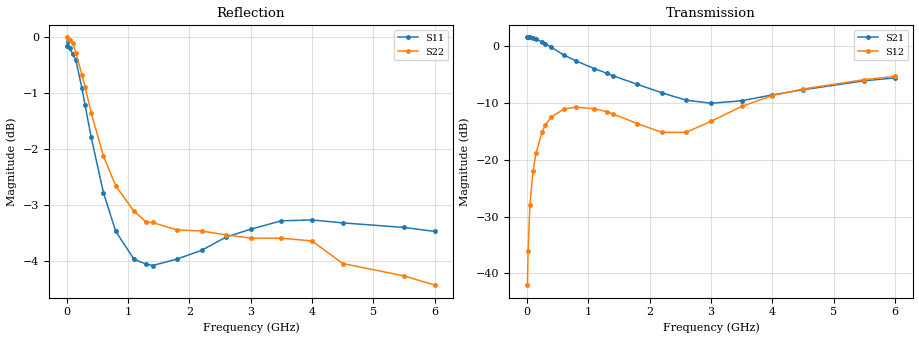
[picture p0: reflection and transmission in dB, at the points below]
! Infineon Technologies  Discrete & RF Semiconductors
! BFS17W
! Si NPN RF Bipolar Junction Transistor in SOT323
! VCE = 0.5 V  IC = 0.3 mA
! Common Emitter S-Parameters:  August  1999
# GHz  S  MA  R  50
!  f  S11  S21  S12  S22
! GHz  MAG  ANG  MAG  ANG  MAG  ANG  MAG  ANG
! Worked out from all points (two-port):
!   36 points, 10 MHz to 6 GHz, reference 50 ohm
!   highest |S21| = 1.55 dB at 20 MHz (marker M1); lowest = -10.0 dB at 3 GHz (marker M2)
!   |S21| within 3 dB of the highest: start of sweep to 586.2 MHz
!   lowest |S11| = -4.1 dB at 1.4 GHz (marker M3), VSWR 4.33, Z = 11.8 - j6.94 ohm
!   |S11| at or under -10 dB: nowhere
!   |S22| runs from -4.4 to 0.0 dB; largest |S21 - S12| = 1.2
!   S11 on the Smith chart (normalised r, x): 10 MHz: 25, -48; 250 MHz: 0.29, -2.11; 600 MHz: 0.26, -0.78; 1.3 GHz: 0.24, -0.18; 3 GHz: 0.23, +0.40; 6 GHz: 0.45, +1.09
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0.01  0.9831 -1.9  1.194 178.9  0.0079 85.2  0.9999 -0.4
0.02  0.9929 -4.4  1.196 176.2  0.0159 86.5  0.997 -1.8
0.05  0.9775 -10.5  1.196 170.0  0.0403 83.8  0.9955 -4.3
0.1  0.9663 -20.7  1.171 160.6  0.0793 75.9  0.9884 -8.6
0.15  0.9544 -31.7  1.156 150.6  0.1156 69.0  0.9687 -12.6
0.25  0.9001 -50.1  1.091 132.8  0.1769 56.7  0.9251 -19.8
0.3  0.8702 -59.1  1.05 124.6  0.2018 51.7  0.9031 -23.0
0.4  0.8141 -75.2  0.976 109.5  0.239 42.0  0.8564 -28.6
0.6  0.7262 -101.5  0.838 85.4  0.2793 27.3  0.783 -37.2
0.8  0.6707 -122.0  0.743 67.4  0.2914 17.2  0.7365 -45.0
1.1  0.6329 -145.4  0.635 47.2  0.2815 6.7  0.6988 -55.9
1.3  0.6268 -158.1  0.579 37.2  0.2653 2.3  0.6834 -63.7
1.4  0.625 -163.3  0.551 33.0  0.2539 0.7  0.683 -67.2
1.8  0.6334 177.3  0.462 20.3  0.2086 0.2  0.6726 -83.2
2.2  0.6449 161.7  0.389 14.4  0.1747 10.6  0.6711 -98.8
2.6  0.6628 147.5  0.335 14.8  0.175 28.7  0.6657 -114.5
3  0.6736 134.9  0.315 19.8  0.2181 40.8  0.6613 -129.0
3.5  0.6853 120.8  0.331 26.4  0.295 43.9  0.6612 -146.6
4  0.6865 109.3  0.373 28.5  0.3677 40.1  0.6575 -163.8
4.5  0.6824 99.3  0.414 27.3  0.4202 34.6  0.6276 -178.5
5.5  0.676 85.0  0.496 20.4  0.5077 24.0  0.6118 158.2
6  0.6705 79.7  0.527 16.2  0.542 18.9  0.6003 148.1
